VERSION 5.7 ;
  NOWIREEXTENSIONATPIN ON ;
  DIVIDERCHAR "/" ;
  BUSBITCHARS "[]" ;
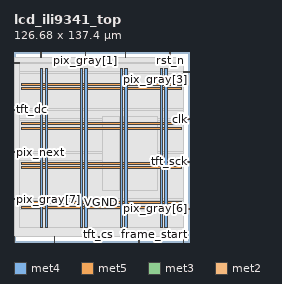
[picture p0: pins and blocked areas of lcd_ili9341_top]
MACRO lcd_ili9341_top
  CLASS BLOCK ;
  FOREIGN lcd_ili9341_top ;
  ORIGIN 0.000 0.000 ;
  SIZE 126.680 BY 137.400 ;
  PIN VGND
    DIRECTION INOUT ;
    USE GROUND ;
    PORT
      LAYER met4 ;
        RECT 22.450 10.640 24.050 125.360 ;
    END
    PORT
      LAYER met4 ;
        RECT 51.315 10.640 52.915 125.360 ;
    END
    PORT
      LAYER met4 ;
        RECT 80.180 10.640 81.780 125.360 ;
    END
    PORT
      LAYER met4 ;
        RECT 109.045 10.640 110.645 125.360 ;
    END
    PORT
      LAYER met5 ;
        RECT 5.280 27.660 121.220 29.260 ;
    END
    PORT
      LAYER met5 ;
        RECT 5.280 56.220 121.220 57.820 ;
    END
    PORT
      LAYER met5 ;
        RECT 5.280 84.780 121.220 86.380 ;
    END
    PORT
      LAYER met5 ;
        RECT 5.280 113.340 121.220 114.940 ;
    END
  END VGND
  PIN VPWR
    DIRECTION INOUT ;
    USE POWER ;
    PORT
      LAYER met4 ;
        RECT 19.150 10.640 20.750 125.360 ;
    END
    PORT
      LAYER met4 ;
        RECT 48.015 10.640 49.615 125.360 ;
    END
    PORT
      LAYER met4 ;
        RECT 76.880 10.640 78.480 125.360 ;
    END
    PORT
      LAYER met4 ;
        RECT 105.745 10.640 107.345 125.360 ;
    END
    PORT
      LAYER met5 ;
        RECT 5.280 24.360 121.220 25.960 ;
    END
    PORT
      LAYER met5 ;
        RECT 5.280 52.920 121.220 54.520 ;
    END
    PORT
      LAYER met5 ;
        RECT 5.280 81.480 121.220 83.080 ;
    END
    PORT
      LAYER met5 ;
        RECT 5.280 110.040 121.220 111.640 ;
    END
  END VPWR
  PIN clk
    DIRECTION INPUT ;
    USE SIGNAL ;
    ANTENNAGATEAREA 0.852000 ;
    PORT
      LAYER met3 ;
        RECT 122.680 88.440 126.680 89.040 ;
    END
  END clk
  PIN frame_start
    DIRECTION OUTPUT TRISTATE ;
    USE SIGNAL ;
    ANTENNADIFFAREA 0.795200 ;
    PORT
      LAYER met2 ;
        RECT 122.450 0.000 122.730 4.000 ;
    END
  END frame_start
  PIN init_done
    DIRECTION OUTPUT TRISTATE ;
    USE SIGNAL ;
    ANTENNADIFFAREA 0.795200 ;
    PORT
      LAYER met3 ;
        RECT 0.000 129.240 4.000 129.840 ;
    END
  END init_done
  PIN pix_gray[0]
    DIRECTION INPUT ;
    USE SIGNAL ;
    PORT
      LAYER met2 ;
        RECT 80.590 133.400 80.870 137.400 ;
    END
  END pix_gray[0]
  PIN pix_gray[1]
    DIRECTION INPUT ;
    USE SIGNAL ;
    PORT
      LAYER met2 ;
        RECT 51.610 133.400 51.890 137.400 ;
    END
  END pix_gray[1]
  PIN pix_gray[2]
    DIRECTION INPUT ;
    USE SIGNAL ;
    ANTENNAGATEAREA 0.196500 ;
    PORT
      LAYER met2 ;
        RECT 0.090 0.000 0.370 4.000 ;
    END
  END pix_gray[2]
  PIN pix_gray[3]
    DIRECTION INPUT ;
    USE SIGNAL ;
    ANTENNAGATEAREA 0.126000 ;
    PORT
      LAYER met3 ;
        RECT 122.680 122.440 126.680 123.040 ;
    END
  END pix_gray[3]
  PIN pix_gray[4]
    DIRECTION INPUT ;
    USE SIGNAL ;
    ANTENNAGATEAREA 0.196500 ;
    PORT
      LAYER met2 ;
        RECT 90.250 0.000 90.530 4.000 ;
    END
  END pix_gray[4]
  PIN pix_gray[5]
    DIRECTION INPUT ;
    USE SIGNAL ;
    ANTENNAGATEAREA 0.196500 ;
    PORT
      LAYER met2 ;
        RECT 29.070 0.000 29.350 4.000 ;
    END
  END pix_gray[5]
  PIN pix_gray[6]
    DIRECTION INPUT ;
    USE SIGNAL ;
    ANTENNAGATEAREA 0.196500 ;
    PORT
      LAYER met3 ;
        RECT 122.680 23.840 126.680 24.440 ;
    END
  END pix_gray[6]
  PIN pix_gray[7]
    DIRECTION INPUT ;
    USE SIGNAL ;
    ANTENNAGATEAREA 0.196500 ;
    PORT
      LAYER met3 ;
        RECT 0.000 30.640 4.000 31.240 ;
    END
  END pix_gray[7]
  PIN pix_next
    DIRECTION OUTPUT TRISTATE ;
    USE SIGNAL ;
    ANTENNADIFFAREA 0.795200 ;
    PORT
      LAYER met3 ;
        RECT 0.000 64.640 4.000 65.240 ;
    END
  END pix_next
  PIN rst_n
    DIRECTION INPUT ;
    USE SIGNAL ;
    ANTENNAGATEAREA 0.213000 ;
    PORT
      LAYER met2 ;
        RECT 112.790 133.400 113.070 137.400 ;
    END
  END rst_n
  PIN tft_cs
    DIRECTION OUTPUT TRISTATE ;
    USE SIGNAL ;
    ANTENNADIFFAREA 0.795200 ;
    PORT
      LAYER met2 ;
        RECT 61.270 0.000 61.550 4.000 ;
    END
  END tft_cs
  PIN tft_dc
    DIRECTION OUTPUT TRISTATE ;
    USE SIGNAL ;
    ANTENNADIFFAREA 0.795200 ;
    PORT
      LAYER met3 ;
        RECT 0.000 95.240 4.000 95.840 ;
    END
  END tft_dc
  PIN tft_mosi
    DIRECTION OUTPUT TRISTATE ;
    USE SIGNAL ;
    ANTENNADIFFAREA 0.795200 ;
    PORT
      LAYER met2 ;
        RECT 19.410 133.400 19.690 137.400 ;
    END
  END tft_mosi
  PIN tft_sck
    DIRECTION OUTPUT TRISTATE ;
    USE SIGNAL ;
    ANTENNADIFFAREA 0.445500 ;
    PORT
      LAYER met3 ;
        RECT 122.680 57.840 126.680 58.440 ;
    END
  END tft_sck
  OBS
      LAYER li1 ;
        RECT 5.520 10.795 120.980 125.205 ;
      LAYER met1 ;
        RECT 0.070 10.640 122.750 125.360 ;
      LAYER met2 ;
        RECT 0.100 133.120 19.130 133.400 ;
        RECT 19.970 133.120 51.330 133.400 ;
        RECT 52.170 133.120 80.310 133.400 ;
        RECT 81.150 133.120 112.510 133.400 ;
        RECT 113.350 133.120 122.720 133.400 ;
        RECT 0.100 4.280 122.720 133.120 ;
        RECT 0.650 4.000 28.790 4.280 ;
        RECT 29.630 4.000 60.990 4.280 ;
        RECT 61.830 4.000 89.970 4.280 ;
        RECT 90.810 4.000 122.170 4.280 ;
      LAYER met3 ;
        RECT 4.400 128.840 122.680 129.690 ;
        RECT 3.990 123.440 122.680 128.840 ;
        RECT 3.990 122.040 122.280 123.440 ;
        RECT 3.990 96.240 122.680 122.040 ;
        RECT 4.400 94.840 122.680 96.240 ;
        RECT 3.990 89.440 122.680 94.840 ;
        RECT 3.990 88.040 122.280 89.440 ;
        RECT 3.990 65.640 122.680 88.040 ;
        RECT 4.400 64.240 122.680 65.640 ;
        RECT 3.990 58.840 122.680 64.240 ;
        RECT 3.990 57.440 122.280 58.840 ;
        RECT 3.990 31.640 122.680 57.440 ;
        RECT 4.400 30.240 122.680 31.640 ;
        RECT 3.990 24.840 122.680 30.240 ;
        RECT 3.990 23.440 122.280 24.840 ;
        RECT 3.990 10.715 122.680 23.440 ;
      LAYER met4 ;
        RECT 63.775 36.895 76.480 90.945 ;
        RECT 78.880 36.895 79.780 90.945 ;
        RECT 82.180 36.895 103.665 90.945 ;
  END
END lcd_ili9341_top
END LIBRARY

